VERSION 5.8 ;
BUSBITCHARS "[]" ;
DIVIDERCHAR "/" ;

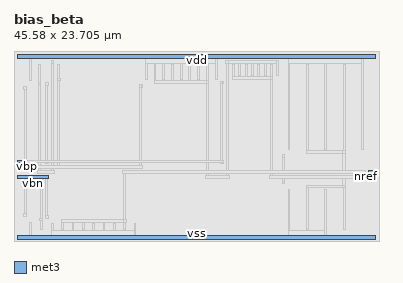
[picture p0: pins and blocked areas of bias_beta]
MACRO bias_beta
  CLASS BLOCK ;
  FOREIGN bias_beta 0 0 ;
  ORIGIN 0 0 ;
  SIZE 45.580 BY 23.705 ;
  SYMMETRY X Y ;
  PIN nref
    DIRECTION OUTPUT ;
    USE SIGNAL ;
    PORT
      LAYER met3 ;
        RECT 44.180 7.815 45.120 8.155 ;
    END
  END nref
  PIN pref
    DIRECTION OUTPUT ;
    USE SIGNAL ;
    PORT
      LAYER met3 ;
        RECT 44.180 8.455 45.120 8.795 ;
    END
  END pref
  PIN vbn
    DIRECTION INPUT ;
    USE SIGNAL ;
    PORT
      LAYER met3 ;
        RECT 0.460 7.815 4.340 8.155 ;
    END
  END vbn
  PIN vbp
    DIRECTION INPUT ;
    USE SIGNAL ;
    PORT
      LAYER met3 ;
        RECT 0.460 9.095 1.400 9.435 ;
    END
  END vbp
  PIN vbpc
    DIRECTION INPUT ;
    USE SIGNAL ;
    PORT
      LAYER met3 ;
        RECT 0.460 9.735 1.400 10.075 ;
    END
  END vbpc
  PIN vdd
    DIRECTION INOUT ;
    USE POWER ;
    PORT
      LAYER met3 ;
        RECT 0.460 22.745 45.120 23.245 ;
    END
  END vdd
  PIN vss
    DIRECTION INOUT ;
    USE GROUND ;
    PORT
      LAYER met3 ;
        RECT 0.460 0.185 45.120 0.685 ;
    END
  END vss
  OBS
    LAYER li1 ;
      RECT 0.000 0.000 45.580 23.705 ;
    LAYER met1 ;
      RECT 5.960 1.455 6.190 2.340 ;
      RECT 8.540 1.455 8.770 2.340 ;
      RECT 11.120 1.455 11.350 2.340 ;
      RECT 5.960 2.340 13.700 2.680 ;
      RECT 13.930 2.345 13.980 2.675 ;
      RECT 13.700 1.455 13.930 2.680 ;
      RECT 3.280 2.860 3.510 2.865 ;
      RECT 3.230 2.530 3.560 2.860 ;
      RECT 3.280 1.455 3.510 2.530 ;
      RECT 3.920 2.860 4.260 3.200 ;
      RECT 1.240 3.045 1.580 3.385 ;
      RECT 4.670 1.265 4.900 2.170 ;
      RECT 7.250 1.265 7.480 2.170 ;
      RECT 9.830 1.265 10.060 2.170 ;
      RECT 12.410 1.265 12.640 2.170 ;
      RECT 14.990 0.685 15.220 2.170 ;
      RECT 4.670 0.685 14.990 1.265 ;
      RECT 1.990 0.685 2.220 2.355 ;
      RECT 34.200 1.265 34.430 6.455 ;
      RECT 39.010 0.185 45.120 0.685 ;
      RECT 38.780 0.185 39.010 6.455 ;
      RECT 34.200 0.185 38.780 1.265 ;
      RECT 0.460 0.185 34.200 0.685 ;
      RECT 36.490 1.455 36.720 6.625 ;
      RECT 36.490 6.625 41.070 6.965 ;
      RECT 41.300 6.630 41.350 6.960 ;
      RECT 41.070 1.455 41.300 6.965 ;
      RECT 33.450 7.145 33.790 7.485 ;
      RECT 33.450 10.445 33.790 10.785 ;
      RECT 1.240 18.945 1.580 19.285 ;
      RECT 15.630 19.180 15.970 19.520 ;
      RECT 3.920 19.445 4.260 19.785 ;
      RECT 25.740 19.620 26.080 19.960 ;
      RECT 3.030 19.470 3.080 19.800 ;
      RECT 3.310 19.470 3.360 19.800 ;
      RECT 3.080 19.465 3.310 21.975 ;
      RECT 5.410 19.970 5.460 20.300 ;
      RECT 5.690 19.970 5.740 20.300 ;
      RECT 5.460 19.965 5.690 21.975 ;
      RECT 17.470 20.040 17.700 21.975 ;
      RECT 19.650 20.040 19.880 21.975 ;
      RECT 21.830 20.040 22.060 21.975 ;
      RECT 24.240 19.705 24.290 20.035 ;
      RECT 24.010 19.700 24.240 21.975 ;
      RECT 17.470 19.700 24.010 20.040 ;
      RECT 27.280 20.480 27.510 21.975 ;
      RECT 28.860 20.480 29.090 21.975 ;
      RECT 30.440 20.480 30.670 21.975 ;
      RECT 32.250 20.145 32.300 20.475 ;
      RECT 32.020 20.140 32.250 21.975 ;
      RECT 27.280 20.140 32.020 20.480 ;
      RECT 36.490 11.305 36.720 21.975 ;
      RECT 41.070 11.305 41.300 21.975 ;
      RECT 41.300 10.970 41.350 11.300 ;
      RECT 36.490 10.965 41.300 11.305 ;
      RECT 4.670 22.500 4.900 22.505 ;
      RECT 4.620 22.170 4.950 22.500 ;
      RECT 4.670 20.475 4.900 22.170 ;
      RECT 26.490 20.650 26.720 22.165 ;
      RECT 28.070 20.650 28.300 22.165 ;
      RECT 29.650 20.650 29.880 22.165 ;
      RECT 31.230 20.650 31.460 22.165 ;
      RECT 26.440 22.170 26.490 22.500 ;
      RECT 26.490 22.165 32.810 22.505 ;
      RECT 32.810 20.650 33.040 22.505 ;
      RECT 16.380 20.210 16.610 22.165 ;
      RECT 18.560 20.210 18.790 22.165 ;
      RECT 20.740 20.210 20.970 22.165 ;
      RECT 22.920 20.210 23.150 22.165 ;
      RECT 34.200 11.475 34.430 22.165 ;
      RECT 38.780 11.475 39.010 22.165 ;
      RECT 1.990 19.975 2.220 22.745 ;
      RECT 16.380 22.165 25.100 22.745 ;
      RECT 25.100 20.210 25.330 22.745 ;
      RECT 0.460 22.745 34.200 23.245 ;
      RECT 34.200 22.165 43.360 23.245 ;
      RECT 43.360 11.475 43.590 22.745 ;
      RECT 43.360 22.745 45.120 23.245 ;
    LAYER met2 ;
      RECT 0.460 0.185 45.120 0.685 ;
      RECT 1.225 7.800 1.595 8.170 ;
      RECT 1.260 3.380 1.560 7.800 ;
      RECT 1.245 3.050 1.575 3.380 ;
      RECT 3.210 7.800 3.580 8.170 ;
      RECT 3.245 2.860 3.545 7.800 ;
      RECT 3.230 2.530 3.560 2.860 ;
      RECT 3.905 7.800 4.275 8.170 ;
      RECT 3.940 3.195 4.240 7.800 ;
      RECT 3.925 2.865 4.255 3.195 ;
      RECT 33.435 7.800 33.805 8.170 ;
      RECT 33.470 7.480 33.770 7.800 ;
      RECT 33.455 7.150 33.785 7.480 ;
      RECT 41.000 7.800 41.370 8.170 ;
      RECT 41.035 6.960 41.335 7.800 ;
      RECT 41.020 6.630 41.350 6.960 ;
      RECT 13.630 8.440 14.000 8.810 ;
      RECT 13.665 2.675 13.965 8.440 ;
      RECT 13.650 2.345 13.980 2.675 ;
      RECT 33.455 10.450 33.785 10.780 ;
      RECT 33.470 8.810 33.770 10.450 ;
      RECT 33.435 8.440 33.805 8.810 ;
      RECT 41.020 10.970 41.350 11.300 ;
      RECT 41.035 8.810 41.335 10.970 ;
      RECT 41.000 8.440 41.370 8.810 ;
      RECT 1.245 18.950 1.575 19.280 ;
      RECT 1.260 9.450 1.560 18.950 ;
      RECT 1.225 9.080 1.595 9.450 ;
      RECT 15.635 19.185 15.965 19.515 ;
      RECT 15.650 9.450 15.950 19.185 ;
      RECT 15.615 9.080 15.985 9.450 ;
      RECT 3.925 19.450 4.255 19.780 ;
      RECT 3.940 10.090 4.240 19.450 ;
      RECT 3.905 9.720 4.275 10.090 ;
      RECT 3.030 19.470 3.360 19.800 ;
      RECT 3.045 8.810 3.345 19.470 ;
      RECT 3.010 8.440 3.380 8.810 ;
      RECT 25.745 19.625 26.075 19.955 ;
      RECT 25.760 10.090 26.060 19.625 ;
      RECT 25.725 9.720 26.095 10.090 ;
      RECT 23.960 19.705 24.290 20.035 ;
      RECT 23.975 8.170 24.275 19.705 ;
      RECT 23.940 7.800 24.310 8.170 ;
      RECT 5.410 19.970 5.740 20.300 ;
      RECT 5.425 9.450 5.725 19.970 ;
      RECT 5.390 9.080 5.760 9.450 ;
      RECT 31.970 20.145 32.300 20.475 ;
      RECT 31.985 8.170 32.285 20.145 ;
      RECT 31.950 7.800 32.320 8.170 ;
      RECT 4.620 22.170 4.950 22.500 ;
      RECT 4.635 8.810 4.935 22.170 ;
      RECT 4.600 8.440 4.970 8.810 ;
      RECT 26.440 22.170 26.770 22.500 ;
      RECT 26.455 8.170 26.755 22.170 ;
      RECT 26.420 7.800 26.790 8.170 ;
      RECT 0.460 22.745 45.120 23.245 ;
    LAYER met3 ;
      RECT 23.875 7.815 26.855 8.155 ;
      RECT 31.885 7.815 43.880 8.155 ;
      RECT 2.945 8.455 5.035 8.795 ;
      RECT 13.565 8.455 43.880 8.795 ;
      RECT 1.700 9.095 16.050 9.435 ;
      RECT 1.700 9.735 26.160 10.075 ;
  END
END bias_beta

END LIBRARY
